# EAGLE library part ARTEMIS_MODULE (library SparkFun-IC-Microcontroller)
Description: The Artemis Module from SparkFun is a Cortex-M4F with BLE 5.0 running up to 96MHz and with as low power as 6uA per MHz (less than 5mW). This is the world's first module to bridge the market between hobbyists and consumer products. We've packaged all the power of a modern microcontroller into a module that is both extremely easy to use but is mass-market ready. The flexibility of the Artemis module starts with our [Arduino core](https://github.com/sparkfun/Arduino_Apollo3). You can program and use the Artemis module just like you would an Uno or any other Arduino. Time to first blink is just 5 minutes away! We built the core from the ground up, making it fast and as light weight as possible.

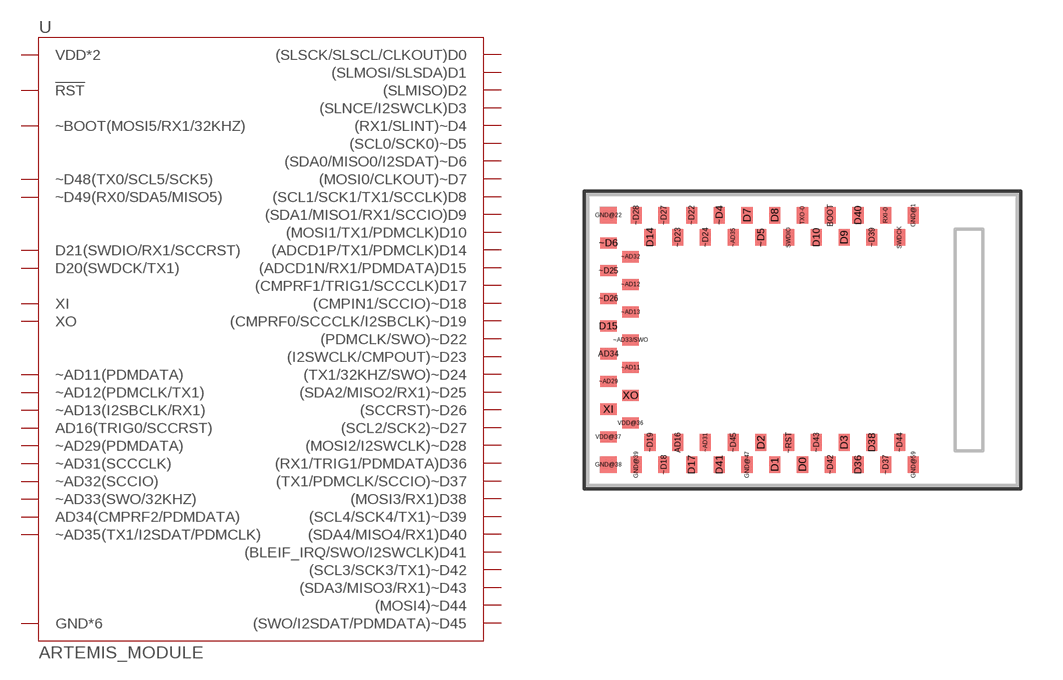
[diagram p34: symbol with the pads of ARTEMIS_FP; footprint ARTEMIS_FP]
Designator prefix U

## ARTEMIS_MODULESMD (PROD_ID: SUB-14415)  [ARTEMIS_FP]
AD16  AD16(TRIG0/SCCRST)
AD34  AD34(CMPRF2/PDMDATA)
BOOT  ~BOOT(MOSI5/RX1/32KHZ)
D0  (SLSCK/SLSCL/CLKOUT)D0
D1  (SLMOSI/SLSDA)D1
D2  (SLMISO)D2
D3  (SLNCE/I2SWCLK)D3
D7  (MOSI0/CLKOUT)~D7
D8  (SCL1/SCK1/TX1/SCCLK)D8
D9  (SDA1/MISO1/RX1/SCCIO)D9
D10  (MOSI1/TX1/PDMCLK)D10
D14  (ADCD1P/TX1/PDMCLK)D14
D15  (ADCD1N/RX1/PDMDATA)D15
D17  (CMPRF1/TRIG1/SCCCLK)D17
D36  (RX1/TRIG1/PDMDATA)D36
D38  (MOSI3/RX1)D38
D40  (SDA4/MISO4/RX1)D40
D41  (BLEIF_IRQ/SWO/I2SWCLK)D41
GND@1  GND*6
GND@22  GND*6
GND@38  GND*6
GND@39  GND*6
GND@47  GND*6
GND@59  GND*6
RXI-0  ~D49(RX0/SDA5/MISO5)
SWDCK  D20(SWDCK/TX1)
SWDIO  D21(SWDIO/RX1/SCCRST)
TXO-0  ~D48(TX0/SCL5/SCK5)
VDD@36  VDD*2
VDD@37  VDD*2
XI  XI
XO  XO
~AD11  ~AD11(PDMDATA)
~AD12  ~AD12(PDMCLK/TX1)
~AD13  ~AD13(I2SBCLK/RX1)
~AD29  ~AD29(PDMDATA)
~AD31  ~AD31(SCCCLK)
~AD32  ~AD32(SCCIO)
~AD33/SWO  ~AD33(SWO/32KHZ)
~AD35  ~AD35(TX1/I2SDAT/PDMCLK)
~D4  (RX1/SLINT)~D4
~D5  (SCL0/SCK0)~D5
~D6  (SDA0/MISO0/I2SDAT)~D6
~D18  (CMPIN1/SCCIO)~D18
~D19  (CMPRF0/SCCCLK/I2SBCLK)~D19
~D22  (PDMCLK/SWO)~D22
~D23  (I2SWCLK/CMPOUT)~D23
~D24  (TX1/32KHZ/SWO)~D24
~D25  (SDA2/MISO2/RX1)~D25
~D26  (SCCRST)~D26
~D27  (SCL2/SCK2)~D27
~D28  (MOSI2/I2SWCLK)~D28
~D37  (TX1/PDMCLK/SCCIO)~D37
~D39  (SCL4/SCK4/TX1)~D39
~D42  (SCL3/SCK3/TX1)~D42
~D43  (SDA3/MISO3/RX1)~D43
~D44  (MOSI4)~D44
~D45  (SWO/I2SDAT/PDMDATA)~D45
~RST  !RST

## Footprint ARTEMIS_FP (pad centres in mm)
smd 0.4 x 0.6: AD16 -4,-3.7; BOOT 1.5,4.5; D0 0.5,-4.5; D1 -0.5,-4.5; D2 -1,-3.7; D3 2,-3.7; D7 -1.5,4.5; D8 -0.5,4.5; D9 2,3.7; D10 1,3.7; D14 -5,3.7; D17 -3.5,-4.5; D36 2.5,-4.5; D38 3,-3.7; D40 2.5,4.5; D41 -2.5,-4.5; GND@1 4.5,4.5; GND@39 -5.5,-4.5; GND@47 -1.5,-4.5; GND@59 4.5,-4.5; RXI-0 3.5,4.5; SWDCK 4,3.7; SWDIO 0,3.7; TXO-0 0.5,4.5; ~AD31 -3,-3.7; ~AD35 -2,3.7; ~D4 -2.5,4.5; ~D5 -1,3.7; ~D18 -4.5,-4.5; ~D19 -5,-3.7; ~D22 -3.5,4.5; ~D23 -4,3.7; ~D24 -3,3.7; ~D27 -4.5,4.5; ~D28 -5.5,4.5; ~D37 3.5,-4.5; ~D39 3,3.7; ~D42 1.5,-4.5; ~D43 1,-3.7; ~D44 4,-3.7; ~D45 -2,-3.7; ~RST 0,-3.7
smd 0.6 x 0.4: AD34 -6.5,-0.5; D15 -6.5,0.5; VDD@36 -5.7,-3; VDD@37 -6.5,-3.5; XI -6.5,-2.5; XO -5.7,-2; ~AD11 -5.7,-1; ~AD12 -5.7,2; ~AD13 -5.7,1; ~AD29 -6.5,-1.5; ~AD32 -5.7,3; ~AD33/SWO -5.7,0; ~D6 -6.5,3.5; ~D25 -6.5,2.5; ~D26 -6.5,1.5
smd 0.6 x 0.6: GND@22 -6.5,4.5; GND@38 -6.5,-4.5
